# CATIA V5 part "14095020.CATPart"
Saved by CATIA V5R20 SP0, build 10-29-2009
Part number: 14095020
Definition: NONE
Nomenclature: 14095020
Source: Unknown
Description: 14095020
Bounding box of the stored display mesh (mm): x -10 to 40, y -61.5 to 51.6, z -51.6 to 51.6
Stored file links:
  C:\Users\Utente\Desktop\IO LAVORO\3D X SITO CF\X SITO\PLASTICA\RF2\14095020.CATPart

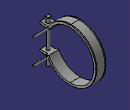
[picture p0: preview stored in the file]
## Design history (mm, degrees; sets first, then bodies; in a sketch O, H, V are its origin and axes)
Body1 "14095020" (main body)
  Solid1: solid without history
